! (c) 2009  Infineon Technologies AG, Munich
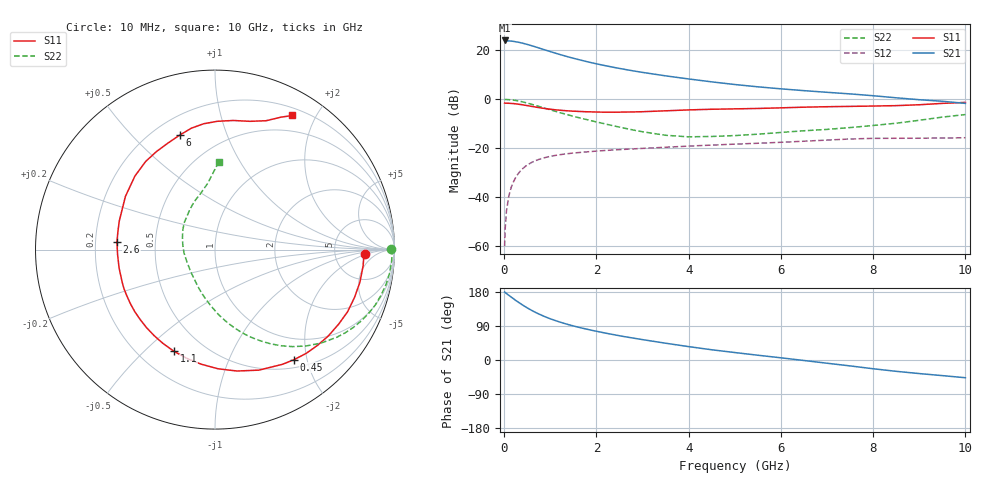
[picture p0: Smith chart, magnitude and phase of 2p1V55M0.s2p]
! Infineon Technologies  Discrete & RF Semiconductors
! BFP420
! VCE =  1.5 V,  IC =  5.0 mA
! Common Emitter S-Parameters:  Nov 2009
# GHz  S  MA  R  50
!  f  S11  S21  S12  S22
! GHz  MAG  ANG  MAG  ANG  MAG  ANG  MAG  ANG
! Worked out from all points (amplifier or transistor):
!   46 points, 10 MHz to 10 GHz, reference 50 ohm
!   highest |S21| = 24.0 dB at 10 MHz (marker M1)
!   |S21| within 3 dB of that: start of sweep to 741.5 MHz
!   unconditionally stable (mu >= 1): 2.97 GHz to end of sweep
!   at 300 MHz: K = 0.10, MSG = 26.9 dB, |S12| = -30.5 dB
!   at 1.7 GHz: K = 0.60, MSG = 18.7 dB, |S12| = -21.6 dB
!   at 10 GHz: K = 1.12, MAG = 4.9 dB, |S12| = -15.7 dB
!   lowest NFmin = 0.66 dB at 900 MHz
!   S11 on the Smith chart (normalised r, x): 10 MHz: 11, -2; 450 MHz: 0.62, -1.78; 1.1 GHz: 0.34, -0.62; 2.6 GHz: 0.29, +0.04; 6 GHz: 0.30, +0.69; 10 GHz: 0.29, +1.69
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0.01  0.8377 -1.7  15.87 179.3  0.001 86.2  0.9824 0.2
0.02  0.8302 -2.5  15.5 178.4  0.0021 91.6  0.9869 -1.5
0.1  0.8277 -12.6  15.55 170.9  0.0104 83.7  0.9812 -7.8
0.2  0.8159 -25.1  15.21 161.9  0.0204 77.1  0.9595 -15.4
0.25  0.8044 -31.1  14.91 157.3  0.0253 74.1  0.9446 -19.1
0.35  0.7817 -43.0  14.31 149.1  0.0341 68.0  0.9058 -26.1
0.45  0.755 -54.3  13.57 141.3  0.0419 62.6  0.8607 -32.6
0.6  0.7147 -70.0  12.37 130.7  0.0515 55.5  0.7876 -41.4
0.7  0.6876 -79.7  11.56 124.4  0.0567 51.5  0.739 -46.6
0.9  0.643 -96.9  10.07 113.5  0.0649 44.9  0.649 -55.6
1.1  0.6109 -112.0  8.797 104.5  0.071 39.9  0.571 -63.2
1.4  0.5784 -131.3  7.285 93.1  0.0778 34.3  0.4759 -73.1
1.7  0.5595 -147.4  6.164 83.9  0.0829 30.4  0.4022 -81.6
2.2  0.5441 -169.3  4.834 70.9  0.09 25.6  0.3118 -94.6
2.6  0.5478 175.6  4.096 61.8  0.0947 22.5  0.2574 -106.0
3.5  0.5805 149.3  3.005 44.3  0.1046 17.2  0.1838 -136.9
4.5  0.6247 128.2  2.265 27.0  0.1159 11.5  0.1738 -174.3
5.5  0.6486 113.9  1.793 12.6  0.1263 6.5  0.1935 159.6
6  0.6677 107.1  1.632 5.8  0.1321 4.0  0.2099 148.7
7  0.7039 95.2  1.386 -8.5  0.1467 -2.4  0.2423 130.3
8.5  0.7409 74.7  1.07 -29.9  0.1596 -16.0  0.3239 104.1
10  0.8619 60.1  0.823 -46.8  0.1639 -24.8  0.487 87.6
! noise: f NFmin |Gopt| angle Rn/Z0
0.9  0.66  0.21  31  0.15
1.8  1.05  0.09  93  0.13
2.4  1.14  0.14  119  0.13
3  1.24  0.17  165  0.11
4  1.41  0.31  -145  0.12
5  1.85  0.38  -119  0.21
6  2.3  0.45  -101  0.36
